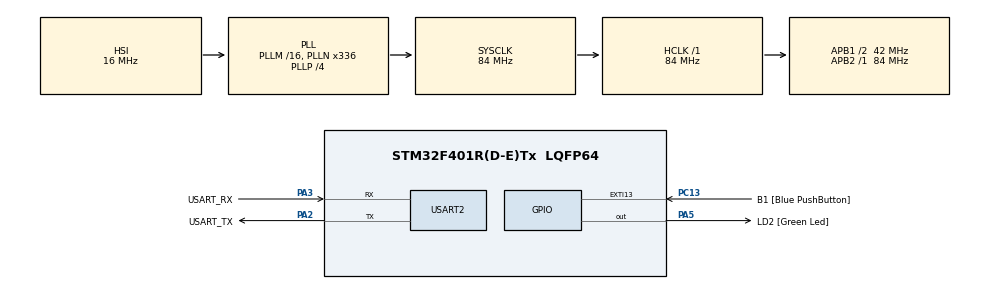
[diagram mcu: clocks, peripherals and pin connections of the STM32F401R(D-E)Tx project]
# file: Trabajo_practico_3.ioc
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FREERTOS.Tasks01=defaultTask,0,128,StartDefaultTask,Default,NULL,Dynamic,NULL,NULL
FREERTOS.configGENERATE_RUN_TIME_STATS=1
FREERTOS.configUSE_STATS_FORMATTING_FUNCTIONS=1
FREERTOS.configUSE_TRACE_FACILITY=1
Mcu.Family=STM32F4
Mcu.Name=STM32F401R(D-E)Tx
Mcu.Package=LQFP64
NVIC.PriorityGroup=NVIC_PRIORITYGROUP_4
NVIC.TIM1_UP_TIM10_IRQn=true\:15\:0\:false\:false\:true\:false\:false\:true\:true
NVIC.TIM2_IRQn=true\:5\:0\:false\:false\:true\:true\:true\:true\:true
NVIC.TimeBase=TIM1_UP_TIM10_IRQn
NVIC.TimeBaseIP=TIM1
PA13.GPIO_Label=TMS
PA13.Mode=Serial_Wire
PA13.Signal=SYS_JTMS-SWDIO
PA14.GPIO_Label=TCK
PA14.Mode=Serial_Wire
PA14.Signal=SYS_JTCK-SWCLK
PA2.GPIO_Label=USART_TX
PA2.GPIO_Mode=GPIO_MODE_AF_PP
PA2.GPIO_PuPd=GPIO_NOPULL
PA2.GPIO_Speed=GPIO_SPEED_FREQ_LOW
PA2.Mode=Asynchronous
PA2.Signal=USART2_TX
PA3.GPIO_Label=USART_RX
PA3.GPIO_Mode=GPIO_MODE_AF_PP
PA3.GPIO_PuPd=GPIO_NOPULL
PA3.GPIO_Speed=GPIO_SPEED_FREQ_LOW
PA3.Mode=Asynchronous
PA3.Signal=USART2_RX
PA5.GPIO_Label=LD2 [Green Led]
PA5.GPIO_Mode=GPIO_MODE_OUTPUT_PP
PA5.GPIO_PuPd=GPIO_NOPULL
PA5.GPIO_Speed=GPIO_SPEED_FREQ_LOW
PA5.Signal=GPIO_Output
PB3.GPIO_Label=SWO
PB3.Signal=SYS_JTDO-SWO
PC13-ANTI_TAMP.GPIO_Label=B1 [Blue PushButton]
PC13-ANTI_TAMP.GPIO_ModeDefaultEXTI=GPIO_MODE_IT_FALLING
PC13-ANTI_TAMP.GPIO_PuPd=GPIO_NOPULL
PC13-ANTI_TAMP.Signal=GPXTI13
PC14-OSC32_IN.Mode=LSE-External-Oscillator
PC14-OSC32_IN.Signal=RCC_OSC32_IN
PC15-OSC32_OUT.Mode=LSE-External-Oscillator
PC15-OSC32_OUT.Signal=RCC_OSC32_OUT
PH0\ -\ OSC_IN.Mode=HSE-External-Clock-Source
PH0\ -\ OSC_IN.Signal=RCC_OSC_IN
PH1\ -\ OSC_OUT.Mode=HSE-External-Clock-Source
PH1\ -\ OSC_OUT.Signal=RCC_OSC_OUT
ProjectManager.HeapSize=0x200
ProjectManager.StackSize=0x400
ProjectManager.TargetToolchain=STM32CubeIDE
RCC.48MHZClocksFreq_Value=48000000
RCC.AHBFreq_Value=84000000
RCC.APB1CLKDivider=RCC_HCLK_DIV2
RCC.APB1Freq_Value=42000000
RCC.APB1TimFreq_Value=84000000
RCC.APB2Freq_Value=84000000
RCC.APB2TimFreq_Value=84000000
RCC.CortexFreq_Value=84000000
RCC.HCLKFreq_Value=84000000
RCC.HSE_VALUE=8000000
RCC.HSI_VALUE=16000000
RCC.PLLN=336
RCC.PLLP=RCC_PLLP_DIV4
RCC.PLLQ=7
RCC.SYSCLKFreq_VALUE=84000000
RCC.SYSCLKSource=RCC_SYSCLKSOURCE_PLLCLK
RCC.VCOOutputFreq_Value=336000000
TIM2.Period=42000-1
TIM2.Prescaler=2-1
USART2.VirtualMode=VM_ASYNC
VP_FREERTOS_VS_CMSIS_V1.Mode=CMSIS_V1
VP_SYS_VS_tim1.Mode=TIM1
VP_TIM2_VS_ClockSourceINT.Mode=Internal
board=NUCLEO-F401RE

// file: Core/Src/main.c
/* USER CODE BEGIN Header */
/**
  ******************************************************************************
  * @file           : main.c
  * @brief          : Main program body
  ******************************************************************************
  * @attention
  *
  * Copyright (c) 2024 STMicroelectronics.
  * All rights reserved.
  *
  * This software is licensed under terms that can be found in the LICENSE file
  * in the root directory of this software component.
  * If no LICENSE file comes with this software, it is provided AS-IS.
  *
  ******************************************************************************
  */
/* USER CODE END Header */
#include "main.h"
#include "string.h"
#include "cmsis_os.h"

/* USER CODE BEGIN Includes */

/* Demo includes. */
#include "logger.h"
#include "dwt.h"

/* Application includes. */
#include "app.h"

/* USER CODE END Includes */

TIM_HandleTypeDef htim2;

UART_HandleTypeDef huart2;

osThreadId defaultTaskHandle;
/* USER CODE BEGIN PV */
volatile unsigned long ulHighFrequencyTimerTicks;

/* USER CODE END PV */

void SystemClock_Config(void);
static void MX_GPIO_Init(void);
static void MX_USART2_UART_Init(void);
static void MX_TIM2_Init(void);
void StartDefaultTask(void const * argument);

/* USER CODE BEGIN 0 */
extern void initialise_monitor_handles(void);

/* USER CODE END 0 */

int main(void)
{
  /* USER CODE BEGIN 1 */
	initialise_monitor_handles();

  /* USER CODE END 1 */

  /* MCU Configuration--------------------------------------------------------*/

  /* Reset of all peripherals, Initializes the Flash interface and the Systick. */
  HAL_Init();

  /* Configure the system clock */
  SystemClock_Config();

  /* Initialize all configured peripherals */
  MX_GPIO_Init();
  MX_USART2_UART_Init();
  MX_TIM2_Init();
  /* USER CODE BEGIN 2 */
  /* Start timer */
	HAL_TIM_Base_Start_IT(&htim2);

    /* add application, ... */
	app_init();

  /* USER CODE END 2 */

  /* USER CODE BEGIN RTOS_QUEUES */
  /* add queues, ... */
	#ifdef _defaultTask_

  /* USER CODE END RTOS_QUEUES */

  /* Create the thread(s) */
  /* definition and creation of defaultTask */
  osThreadDef(defaultTask, StartDefaultTask, osPriorityNormal, 0, 128);
  defaultTaskHandle = osThreadCreate(osThread(defaultTask), NULL);

  /* USER CODE BEGIN RTOS_THREADS */
	#endif

  /* add threads, ... */
  /* USER CODE END RTOS_THREADS */

  /* Start scheduler */
  osKernelStart();

  /* We should never get here as control is now taken by the scheduler */
  /* Infinite loop */
  while (1)
  {

  }
}

void SystemClock_Config(void)
{
  RCC_OscInitTypeDef RCC_OscInitStruct = {0};
  RCC_ClkInitTypeDef RCC_ClkInitStruct = {0};

  /** Configure the main internal regulator output voltage
  */
  __HAL_RCC_PWR_CLK_ENABLE();
  __HAL_PWR_VOLTAGESCALING_CONFIG(PWR_REGULATOR_VOLTAGE_SCALE2);

  /** Initializes the RCC Oscillators according to the specified parameters
  * in the RCC_OscInitTypeDef structure.
  */
  RCC_OscInitStruct.OscillatorType = RCC_OSCILLATORTYPE_HSI;
  RCC_OscInitStruct.HSIState = RCC_HSI_ON;
  RCC_OscInitStruct.HSICalibrationValue = RCC_HSICALIBRATION_DEFAULT;
  RCC_OscInitStruct.PLL.PLLState = RCC_PLL_ON;
  RCC_OscInitStruct.PLL.PLLSource = RCC_PLLSOURCE_HSI;
  RCC_OscInitStruct.PLL.PLLM = 16;
  RCC_OscInitStruct.PLL.PLLN = 336;
  RCC_OscInitStruct.PLL.PLLP = RCC_PLLP_DIV4;
  RCC_OscInitStruct.PLL.PLLQ = 7;
  if (HAL_RCC_OscConfig(&RCC_OscInitStruct) != HAL_OK)
  {
    Error_Handler();
  }

  /** Initializes the CPU, AHB and APB buses clocks
  */
  RCC_ClkInitStruct.ClockType = RCC_CLOCKTYPE_HCLK|RCC_CLOCKTYPE_SYSCLK
                              |RCC_CLOCKTYPE_PCLK1|RCC_CLOCKTYPE_PCLK2;
  RCC_ClkInitStruct.SYSCLKSource = RCC_SYSCLKSOURCE_PLLCLK;
  RCC_ClkInitStruct.AHBCLKDivider = RCC_SYSCLK_DIV1;
  RCC_ClkInitStruct.APB1CLKDivider = RCC_HCLK_DIV2;
  RCC_ClkInitStruct.APB2CLKDivider = RCC_HCLK_DIV1;

  if (HAL_RCC_ClockConfig(&RCC_ClkInitStruct, FLASH_LATENCY_2) != HAL_OK)
  {
    Error_Handler();
  }
}

static void MX_TIM2_Init(void)
{

  TIM_ClockConfigTypeDef sClockSourceConfig = {0};
  TIM_MasterConfigTypeDef sMasterConfig = {0};

  htim2.Instance = TIM2;
  htim2.Init.Prescaler = 2-1;
  htim2.Init.CounterMode = TIM_COUNTERMODE_UP;
  htim2.Init.Period = 42000-1;
  htim2.Init.ClockDivision = TIM_CLOCKDIVISION_DIV1;
  htim2.Init.AutoReloadPreload = TIM_AUTORELOAD_PRELOAD_DISABLE;
  if (HAL_TIM_Base_Init(&htim2) != HAL_OK)
  {
    Error_Handler();
  }
  sClockSourceConfig.ClockSource = TIM_CLOCKSOURCE_INTERNAL;
  if (HAL_TIM_ConfigClockSource(&htim2, &sClockSourceConfig) != HAL_OK)
  {
    Error_Handler();
  }
  sMasterConfig.MasterOutputTrigger = TIM_TRGO_RESET;
  sMasterConfig.MasterSlaveMode = TIM_MASTERSLAVEMODE_DISABLE;
  if (HAL_TIMEx_MasterConfigSynchronization(&htim2, &sMasterConfig) != HAL_OK)
  {
    Error_Handler();
  }

}

static void MX_USART2_UART_Init(void)
{

  huart2.Instance = USART2;
  huart2.Init.BaudRate = 115200;
  huart2.Init.WordLength = UART_WORDLENGTH_8B;
  huart2.Init.StopBits = UART_STOPBITS_1;
  huart2.Init.Parity = UART_PARITY_NONE;
  huart2.Init.Mode = UART_MODE_TX_RX;
  huart2.Init.HwFlowCtl = UART_HWCONTROL_NONE;
  huart2.Init.OverSampling = UART_OVERSAMPLING_16;
  if (HAL_UART_Init(&huart2) != HAL_OK)
  {
    Error_Handler();
  }

}

static void MX_GPIO_Init(void)
{
  GPIO_InitTypeDef GPIO_InitStruct = {0};

  /* GPIO Ports Clock Enable */
  __HAL_RCC_GPIOC_CLK_ENABLE();
  __HAL_RCC_GPIOH_CLK_ENABLE();
  __HAL_RCC_GPIOA_CLK_ENABLE();
  __HAL_RCC_GPIOB_CLK_ENABLE();

  /*Configure GPIO pin Output Level */
  HAL_GPIO_WritePin(GPIOA, LED_R_Pin|LED_G_Pin|LED_B_Pin|LD2_Pin, GPIO_PIN_RESET);

  /*Configure GPIO pin : B1_Pin */
  GPIO_InitStruct.Pin = B1_Pin;
  GPIO_InitStruct.Mode = GPIO_MODE_IT_FALLING;
  GPIO_InitStruct.Pull = GPIO_NOPULL;
  HAL_GPIO_Init(B1_GPIO_Port, &GPIO_InitStruct);

  /*Configure GPIO pins : LED_R_Pin LED_G_Pin LED_B_Pin LD2_Pin */
  GPIO_InitStruct.Pin = LED_R_Pin|LED_G_Pin|LED_B_Pin|LD2_Pin;
  GPIO_InitStruct.Mode = GPIO_MODE_OUTPUT_PP;
  GPIO_InitStruct.Pull = GPIO_NOPULL;
  GPIO_InitStruct.Speed = GPIO_SPEED_FREQ_LOW;
  HAL_GPIO_Init(GPIOA, &GPIO_InitStruct);

}

/* USER CODE BEGIN 4 */
/* Functions needed when configGENERATE_RUN_TIME_STATS is on */
void configureTimerForRunTimeStats(void)
{
    ulHighFrequencyTimerTicks = 0;
}

unsigned long getRunTimeCounterValue(void)
{
	return ulHighFrequencyTimerTicks;
}

/* Hook Functions */
void vApplicationIdleHook(void)
{
	/* The idle task can optionally call an application defined hook (or callback)
	   function - the idle hook. The idle task runs at the very lowest priority,
	   so such an idle hook function will only get executed when there are no tasks
	   of higher priority that are able to run. This makes the idle hook function
	   an ideal place to put the processor into a low power state - providing an
	   automatic power saving whenever there is no processing to be performed.
	   The idle hook will only get called if configUSE_IDLE_HOOK is set to 1
	   https://www.freertos.org/a00016.html
	   The idle hook is called repeatedly as long as the idle task is running. It
	   is paramount that the idle hook function does not call any API functions
	   that could cause it to block.*/
	LOGGER_LOG("  +\r\n");

}

void vApplicationTickHook(void)
{
	/* The tick interrupt can optionally call an application defined hook (or callback)
	   function - the tick hook.
	   The tick hook will only get called if configUSE_TICK_HOOK is set to 1
	   https://www.freertos.org/a00016.html
	   vApplicationTickHook() executes from within an ISR so must be very short, not use
	   much stack, and not call any API functions that don't end in "FromISR" or "FROM_ISR".*/
	LOGGER_LOG("  -\r\n");
}

void vApplicationStackOverflowHook(xTaskHandle xTask, signed char *pcTaskName)
{
	/* Run time stack overflow checking is performed if
	   configCHECK_FOR_STACK_OVERFLOW is defined to 1 or 2. This hook function is
	   called if a stack overflow is detected.
	   https://www.freertos.org/Stacks-and-stack-overflow-checking.html */
	LOGGER_LOG(" Application Stack Overflow!! on Task: %s\r\n", ( char* )pcTaskName );

    taskENTER_CRITICAL();
    configASSERT( 0 );   /* hang the execution for debugging purposes */
    taskEXIT_CRITICAL();
}

/* USER CODE END 4 */

void StartDefaultTask(void const * argument)
{
  for(;;)
  {
    osDelay(1);
  }
}

void HAL_TIM_PeriodElapsedCallback(TIM_HandleTypeDef *htim)
{
  if (htim->Instance == TIM1) {
    HAL_IncTick();
  }
  /* USER CODE BEGIN Callback 1 */
	if (htim->Instance == TIM2)
	{
		ulHighFrequencyTimerTicks++;
	}

  /* USER CODE END Callback 1 */
}

void Error_Handler(void)
{
  __disable_irq();
  while (1)
  {
  }
}
